VERSION 5.7 ;
  NOWIREEXTENSIONATPIN ON ;
  DIVIDERCHAR "/" ;
  BUSBITCHARS "[]" ;
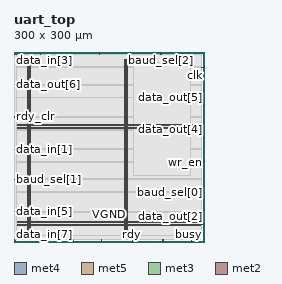
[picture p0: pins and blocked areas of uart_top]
MACRO uart_top
  CLASS BLOCK ;
  FOREIGN uart_top ;
  ORIGIN 0.000 0.000 ;
  SIZE 300.000 BY 300.000 ;
  PIN VGND
    DIRECTION INOUT ;
    USE GROUND ;
    PORT
      LAYER met4 ;
        RECT 24.340 10.640 25.940 288.560 ;
    END
    PORT
      LAYER met4 ;
        RECT 177.940 10.640 179.540 288.560 ;
    END
    PORT
      LAYER met5 ;
        RECT 5.280 30.030 294.640 31.630 ;
    END
    PORT
      LAYER met5 ;
        RECT 5.280 183.210 294.640 184.810 ;
    END
  END VGND
  PIN VPWR
    DIRECTION INOUT ;
    USE POWER ;
    PORT
      LAYER met4 ;
        RECT 21.040 10.640 22.640 288.560 ;
    END
    PORT
      LAYER met4 ;
        RECT 174.640 10.640 176.240 288.560 ;
    END
    PORT
      LAYER met5 ;
        RECT 5.280 26.730 294.640 28.330 ;
    END
    PORT
      LAYER met5 ;
        RECT 5.280 179.910 294.640 181.510 ;
    END
  END VPWR
  PIN baud_sel[0]
    DIRECTION INPUT ;
    USE SIGNAL ;
    ANTENNAGATEAREA 0.159000 ;
    PORT
      LAYER met3 ;
        RECT 296.000 78.240 300.000 78.840 ;
    END
  END baud_sel[0]
  PIN baud_sel[1]
    DIRECTION INPUT ;
    USE SIGNAL ;
    ANTENNAGATEAREA 0.213000 ;
    PORT
      LAYER met3 ;
        RECT 0.000 98.640 4.000 99.240 ;
    END
  END baud_sel[1]
  PIN baud_sel[2]
    DIRECTION INPUT ;
    USE SIGNAL ;
    ANTENNAGATEAREA 0.213000 ;
    PORT
      LAYER met2 ;
        RECT 231.930 296.000 232.210 300.000 ;
    END
  END baud_sel[2]
  PIN busy
    DIRECTION OUTPUT TRISTATE ;
    USE SIGNAL ;
    ANTENNADIFFAREA 0.795200 ;
    PORT
      LAYER met2 ;
        RECT 280.230 0.000 280.510 4.000 ;
    END
  END busy
  PIN clk
    DIRECTION INPUT ;
    USE SIGNAL ;
    ANTENNAGATEAREA 0.852000 ;
    PORT
      LAYER met3 ;
        RECT 296.000 275.440 300.000 276.040 ;
    END
  END clk
  PIN data_in[0]
    DIRECTION INPUT ;
    USE SIGNAL ;
    ANTENNAGATEAREA 0.126000 ;
    PORT
      LAYER met2 ;
        RECT 90.250 296.000 90.530 300.000 ;
    END
  END data_in[0]
  PIN data_in[1]
    DIRECTION INPUT ;
    USE SIGNAL ;
    ANTENNAGATEAREA 0.196500 ;
    PORT
      LAYER met3 ;
        RECT 0.000 146.240 4.000 146.840 ;
    END
  END data_in[1]
  PIN data_in[2]
    DIRECTION INPUT ;
    USE SIGNAL ;
    ANTENNAGATEAREA 0.213000 ;
    PORT
      LAYER met2 ;
        RECT 277.010 296.000 277.290 300.000 ;
    END
  END data_in[2]
  PIN data_in[3]
    DIRECTION INPUT ;
    USE SIGNAL ;
    ANTENNAGATEAREA 0.213000 ;
    PORT
      LAYER met2 ;
        RECT 41.950 296.000 42.230 300.000 ;
    END
  END data_in[3]
  PIN data_in[4]
    DIRECTION INPUT ;
    USE SIGNAL ;
    ANTENNAGATEAREA 0.196500 ;
    PORT
      LAYER met2 ;
        RECT 138.550 0.000 138.830 4.000 ;
    END
  END data_in[4]
  PIN data_in[5]
    DIRECTION INPUT ;
    USE SIGNAL ;
    ANTENNAGATEAREA 0.213000 ;
    PORT
      LAYER met3 ;
        RECT 0.000 47.640 4.000 48.240 ;
    END
  END data_in[5]
  PIN data_in[6]
    DIRECTION INPUT ;
    USE SIGNAL ;
    ANTENNAGATEAREA 0.213000 ;
    PORT
      LAYER met2 ;
        RECT 235.150 0.000 235.430 4.000 ;
    END
  END data_in[6]
  PIN data_in[7]
    DIRECTION INPUT ;
    USE SIGNAL ;
    ANTENNAGATEAREA 0.213000 ;
    PORT
      LAYER met2 ;
        RECT 0.090 0.000 0.370 4.000 ;
    END
  END data_in[7]
  PIN data_out[0]
    DIRECTION OUTPUT TRISTATE ;
    USE SIGNAL ;
    ANTENNADIFFAREA 0.795200 ;
    PORT
      LAYER met2 ;
        RECT 45.170 0.000 45.450 4.000 ;
    END
  END data_out[0]
  PIN data_out[1]
    DIRECTION OUTPUT TRISTATE ;
    USE SIGNAL ;
    ANTENNADIFFAREA 0.795200 ;
    PORT
      LAYER met2 ;
        RECT 135.330 296.000 135.610 300.000 ;
    END
  END data_out[1]
  PIN data_out[2]
    DIRECTION OUTPUT TRISTATE ;
    USE SIGNAL ;
    ANTENNADIFFAREA 0.795200 ;
    PORT
      LAYER met3 ;
        RECT 296.000 27.240 300.000 27.840 ;
    END
  END data_out[2]
  PIN data_out[3]
    DIRECTION OUTPUT TRISTATE ;
    USE SIGNAL ;
    ANTENNADIFFAREA 0.795200 ;
    PORT
      LAYER met2 ;
        RECT 93.470 0.000 93.750 4.000 ;
    END
  END data_out[3]
  PIN data_out[4]
    DIRECTION OUTPUT TRISTATE ;
    USE SIGNAL ;
    ANTENNADIFFAREA 0.445500 ;
    PORT
      LAYER met3 ;
        RECT 296.000 176.840 300.000 177.440 ;
    END
  END data_out[4]
  PIN data_out[5]
    DIRECTION OUTPUT TRISTATE ;
    USE SIGNAL ;
    ANTENNADIFFAREA 0.445500 ;
    PORT
      LAYER met3 ;
        RECT 296.000 227.840 300.000 228.440 ;
    END
  END data_out[5]
  PIN data_out[6]
    DIRECTION OUTPUT TRISTATE ;
    USE SIGNAL ;
    ANTENNADIFFAREA 0.795200 ;
    PORT
      LAYER met3 ;
        RECT 0.000 248.240 4.000 248.840 ;
    END
  END data_out[6]
  PIN data_out[7]
    DIRECTION OUTPUT TRISTATE ;
    USE SIGNAL ;
    ANTENNADIFFAREA 0.795200 ;
    PORT
      LAYER met2 ;
        RECT 183.630 296.000 183.910 300.000 ;
    END
  END data_out[7]
  PIN rdy
    DIRECTION OUTPUT TRISTATE ;
    USE SIGNAL ;
    ANTENNADIFFAREA 0.795200 ;
    PORT
      LAYER met2 ;
        RECT 186.850 0.000 187.130 4.000 ;
    END
  END rdy
  PIN rdy_clr
    DIRECTION INPUT ;
    USE SIGNAL ;
    ANTENNAGATEAREA 0.213000 ;
    PORT
      LAYER met3 ;
        RECT 0.000 197.240 4.000 197.840 ;
    END
  END rdy_clr
  PIN rst
    DIRECTION INPUT ;
    USE SIGNAL ;
    ANTENNAGATEAREA 0.213000 ;
    PORT
      LAYER met3 ;
        RECT 0.000 295.840 4.000 296.440 ;
    END
  END rst
  PIN wr_en
    DIRECTION INPUT ;
    USE SIGNAL ;
    ANTENNAGATEAREA 0.126000 ;
    PORT
      LAYER met3 ;
        RECT 296.000 125.840 300.000 126.440 ;
    END
  END wr_en
  OBS
      LAYER li1 ;
        RECT 5.520 10.795 294.400 288.405 ;
      LAYER met1 ;
        RECT 0.070 10.640 294.790 288.560 ;
      LAYER met2 ;
        RECT 0.100 295.720 41.670 296.000 ;
        RECT 42.510 295.720 89.970 296.000 ;
        RECT 90.810 295.720 135.050 296.000 ;
        RECT 135.890 295.720 183.350 296.000 ;
        RECT 184.190 295.720 231.650 296.000 ;
        RECT 232.490 295.720 276.730 296.000 ;
        RECT 277.570 295.720 294.770 296.000 ;
        RECT 0.100 4.280 294.770 295.720 ;
        RECT 0.650 4.000 44.890 4.280 ;
        RECT 45.730 4.000 93.190 4.280 ;
        RECT 94.030 4.000 138.270 4.280 ;
        RECT 139.110 4.000 186.570 4.280 ;
        RECT 187.410 4.000 234.870 4.280 ;
        RECT 235.710 4.000 279.950 4.280 ;
        RECT 280.790 4.000 294.770 4.280 ;
      LAYER met3 ;
        RECT 4.400 295.440 296.000 296.290 ;
        RECT 4.000 276.440 296.000 295.440 ;
        RECT 4.000 275.040 295.600 276.440 ;
        RECT 4.000 249.240 296.000 275.040 ;
        RECT 4.400 247.840 296.000 249.240 ;
        RECT 4.000 228.840 296.000 247.840 ;
        RECT 4.000 227.440 295.600 228.840 ;
        RECT 4.000 198.240 296.000 227.440 ;
        RECT 4.400 196.840 296.000 198.240 ;
        RECT 4.000 177.840 296.000 196.840 ;
        RECT 4.000 176.440 295.600 177.840 ;
        RECT 4.000 147.240 296.000 176.440 ;
        RECT 4.400 145.840 296.000 147.240 ;
        RECT 4.000 126.840 296.000 145.840 ;
        RECT 4.000 125.440 295.600 126.840 ;
        RECT 4.000 99.640 296.000 125.440 ;
        RECT 4.400 98.240 296.000 99.640 ;
        RECT 4.000 79.240 296.000 98.240 ;
        RECT 4.000 77.840 295.600 79.240 ;
        RECT 4.000 48.640 296.000 77.840 ;
        RECT 4.400 47.240 296.000 48.640 ;
        RECT 4.000 28.240 296.000 47.240 ;
        RECT 4.000 26.840 295.600 28.240 ;
        RECT 4.000 10.715 296.000 26.840 ;
      LAYER met4 ;
        RECT 187.975 105.575 279.385 283.385 ;
  END
END uart_top
END LIBRARY

